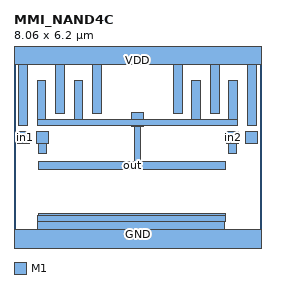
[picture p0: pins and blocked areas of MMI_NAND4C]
MACRO MMI_NAND4C
	CLASS CORE ;
	FOREIGN MMI_NAND4C 0 0 ;
	SIZE 8.06 BY 6.2 ;
	SYMMETRY X Y ;
	SITE CORE1 ;
	PIN out
		DIRECTION output ;
		USE SIGNAL ;
		PORT
			LAYER M1 ;
			RECT 0.755 3.995 1.04 5.285 ;
			LAYER M1 ;
			RECT 1.96 3.995 2.245 5.285 ;
			LAYER M1 ;
			RECT 3.84 3.995 4.22 4.23 ;
			LAYER M1 ;
			RECT 5.805 3.995 6.09 5.285 ;
			LAYER M1 ;
			RECT 7.015 3.995 7.3 5.285 ;
			LAYER M1 ;
			RECT 0.755 3.805 7.3 3.995 ;
			LAYER M1 ;
			RECT 3.84 3.78 4.22 3.805 ;
			LAYER M1 ;
			RECT 3.92 2.635 4.115 3.78 ;
			LAYER M1 ;
			RECT 0.815 2.355 6.915 2.635 ;
		END
		AntennaDiffArea 5.259475 ;
	END out
	PIN in1
		DIRECTION input ;
		USE SIGNAL ;
		PORT
			LAYER M1 ;
			RECT 0.12 3.22 0.5 3.6 ;
		END
		AntennaGateArea 1.392 ;
	END in1
	PIN GND
		DIRECTION inout ;
		USE GROUND ;
		PORT
			LAYER M1 ;
			RECT 0.815 0.855 6.915 0.935 ;
			LAYER M1 ;
			RECT 0.755 0.655 6.915 0.855 ;
			LAYER M1 ;
			RECT 0.755 0.42 6.855 0.655 ;
			LAYER M1 ;
			RECT 0 -0.42 8.06 0.42 ;
		END
	END GND
	PIN in2
		DIRECTION input ;
		USE SIGNAL ;
		PORT
			LAYER M1 ;
			RECT 6.94 3.22 7.32 3.6 ;
			LAYER M1 ;
			RECT 6.99 2.89 7.27 3.22 ;
		END
		AntennaGateArea 1.392 ;
	END in2
	PIN VDD
		DIRECTION inout ;
		USE POWER ;
		PORT
			LAYER M1 ;
			RECT 0 5.78 8.06 6.62 ;
			LAYER M1 ;
			RECT 0.15 3.81 0.43 5.78 ;
			LAYER M1 ;
			RECT 1.36 4.195 1.64 5.78 ;
			LAYER M1 ;
			RECT 2.565 4.195 2.845 5.78 ;
			LAYER M1 ;
			RECT 5.205 4.195 5.485 5.78 ;
			LAYER M1 ;
			RECT 6.41 4.195 6.69 5.78 ;
			LAYER M1 ;
			RECT 7.62 3.81 7.9 5.78 ;
		END
	END VDD
	PIN in3
		DIRECTION input ;
		USE SIGNAL ;
		PORT
			LAYER M1 ;
			RECT 7.56 3.22 7.94 3.6 ;
		END
		AntennaGateArea 1.392 ;
	END in3
	PIN in0
		DIRECTION input ;
		USE SIGNAL ;
		PORT
			LAYER M1 ;
			RECT 0.74 3.22 1.12 3.6 ;
			LAYER M1 ;
			RECT 0.79 2.895 1.07 3.22 ;
		END
		AntennaGateArea 1.392 ;
	END in0
	OBS
	END
END MMI_NAND4C
